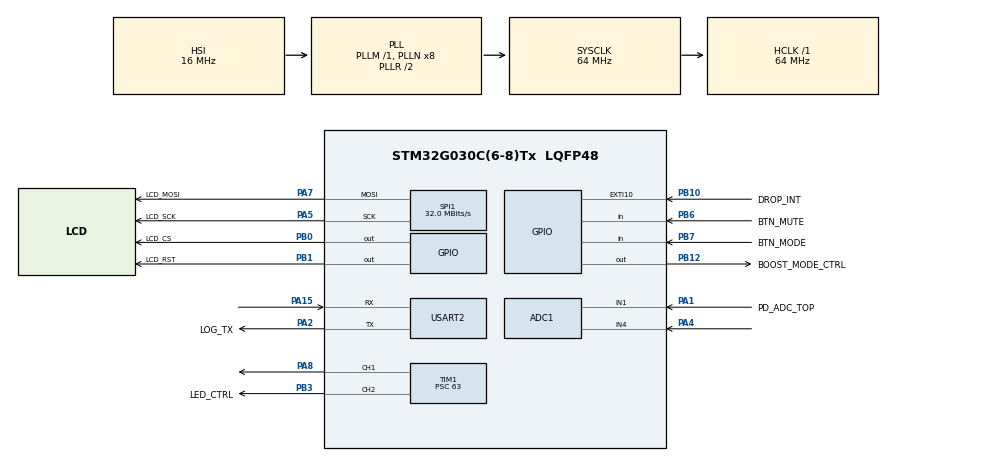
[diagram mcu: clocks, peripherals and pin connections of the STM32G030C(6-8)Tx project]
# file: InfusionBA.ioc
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ADC1.Channel-0\#ChannelRegularConversion=ADC_CHANNEL_1
ADC1.NbrOfConversionFlag=1
ADC1.Rank-0\#ChannelRegularConversion=1
ADC1.SamplingTime-0\#ChannelRegularConversion=ADC_SAMPLINGTIME_COMMON_1
ADC1.SelectedChannel=ADC_CHANNEL_1|ADC_CHANNEL_4
ADC1.master=1
Mcu.Family=STM32G0
Mcu.Name=STM32G030C(6-8)Tx
Mcu.Package=LQFP48
PA13.Mode=Serial_Wire
PA13.Signal=SYS_SWDIO
PA14-BOOT0.Mode=Serial_Wire
PA14-BOOT0.Signal=SYS_SWCLK
PA15.Mode=Asynchronous
PA15.Signal=USART2_RX
PA2.GPIO_Label=LOG_TX
PA2.Mode=Asynchronous
PA2.Signal=USART2_TX
PA1.GPIO_Label=PD_ADC_TOP
PA1.Mode=IN1
PA1.Signal=ADC1_IN1
PA4.Mode=IN4
PA4.Signal=ADC1_IN4
PA5.GPIO_Label=LCD_SCK
PA5.Mode=TX_Only_Simplex_Unidirect_Master
PA5.Signal=SPI1_SCK
PA7.GPIO_Label=LCD_MOSI
PA7.Mode=TX_Only_Simplex_Unidirect_Master
PA7.Signal=SPI1_MOSI
PA8.Signal=S_TIM1_CH1
PB0.GPIO_Label=LCD_CS
PB0.GPIO_ModeDefaultOutputPP=GPIO_MODE_OUTPUT_PP
PB0.GPIO_PuPd=GPIO_PULLUP
PB0.GPIO_Speed=GPIO_SPEED_FREQ_HIGH
PB0.Signal=GPIO_Output
PB1.GPIO_Label=LCD_RST
PB1.GPIO_ModeDefaultOutputPP=GPIO_MODE_OUTPUT_PP
PB1.GPIO_PuPd=GPIO_NOPULL
PB1.GPIO_Speed=GPIO_SPEED_FREQ_MEDIUM
PB1.Signal=GPIO_Output
PB10.GPIO_Label=DROP_INT
PB10.GPIO_ModeDefaultEXTI=GPIO_MODE_IT_FALLING
PB10.Signal=GPXTI10
PB12.GPIO_Label=BOOST_MODE_CTRL
PB12.GPIO_Speed=GPIO_SPEED_FREQ_MEDIUM
PB12.PinState=GPIO_PIN_SET
PB12.Signal=GPIO_Output
PB3.GPIO_Label=LED_CTRL
PB3.Signal=S_TIM1_CH2
PB6.GPIO_Label=BTN_MUTE
PB6.GPIO_PuPd=GPIO_PULLUP
PB6.Signal=GPIO_Input
PB7.GPIO_Label=BTN_MODE
PB7.GPIO_PuPd=GPIO_PULLUP
PB7.Signal=GPIO_Input
PC14-OSC32_IN\ (PC14).GPIO_Label=OSC32_IN
PC14-OSC32_IN\ (PC14).Mode=LSE-External-Oscillator
PC14-OSC32_IN\ (PC14).Signal=RCC_OSC32_IN
PC15-OSC32_OUT\ (PC15).GPIO_Label=OSC32_OUT
PC15-OSC32_OUT\ (PC15).Mode=LSE-External-Oscillator
PC15-OSC32_OUT\ (PC15).Signal=RCC_OSC32_OUT
ProjectManager.HeapSize=0x200
ProjectManager.StackSize=0x400
ProjectManager.TargetToolchain=STM32CubeIDE
RCC.ADCFreq_Value=64000000
RCC.AHBFreq_Value=64000000
RCC.CortexFreq_Value=64000000
RCC.EXTERNAL_CLOCK_VALUE=12288000
RCC.HCLKFreq_Value=64000000
RCC.HSE_VALUE=8000000
RCC.HSI_VALUE=16000000
RCC.SYSCLKFreq_VALUE=64000000
RCC.SYSCLKSource=RCC_SYSCLKSOURCE_PLLCLK
RCC.VCOOutputFreq_Value=128000000
SH.S_TIM1_CH1.0=TIM1_CH1,PWM Generation1 CH1
SH.S_TIM1_CH2.0=TIM1_CH2,PWM Generation2 CH2
SPI1.CalculateBaudRate=32.0 MBits/s
SPI1.Direction=SPI_DIRECTION_2LINES
SPI1.Mode=SPI_MODE_MASTER
SPI1.VirtualType=VM_MASTER
TIM1.AutoReloadPreload=TIM_AUTORELOAD_PRELOAD_ENABLE
TIM1.Channel-PWM\ Generation1\ CH1=TIM_CHANNEL_1
TIM1.Channel-PWM\ Generation2\ CH2=TIM_CHANNEL_2
TIM1.Period=249
TIM1.Prescaler=63
TIM1.Pulse-PWM\ Generation1\ CH1=0
USART2.VirtualMode-Asynchronous=VM_ASYNC
VP_RTC_VS_RTC_Activate.Mode=RTC_Enabled
board=custom

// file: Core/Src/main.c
/* USER CODE BEGIN Header */
/**
  ******************************************************************************
  * @file           : main.c
  * @brief          : Main program body
  ******************************************************************************
  * @attention
  *
  * Copyright (c) 2025 STMicroelectronics.
  * All rights reserved.
  *
  * This software is licensed under terms that can be found in the LICENSE file
  * in the root directory of this software component.
  * If no LICENSE file comes with this software, it is provided AS-IS.
  *
  ******************************************************************************
  */
/* USER CODE END Header */
#include "main.h"

/* USER CODE BEGIN PD */
#define BTN_MINUS_Pin GPIO_PIN_6
#define BTN_PLUS_Pin  GPIO_PIN_7
#define BTN_MODE_Pin  GPIO_PIN_8
#define BTN_MUTE_Pin  GPIO_PIN_9
#define BTN_PORT      GPIOB

/* ---------------- EA DOGS102 SPI DRIVER ---------------- */
#define DOG_CS_PORT   LCD_CS_GPIO_Port   // PB?
#define DOG_CS_PIN    LCD_CS_Pin
#define DOG_RST_PORT  GPIOB
#define DOG_RST_PIN   LCD_RST_Pin
#define DOG_CD_PORT   GPIOB             // D/C# wired to BOOST_MODE_CTRL_Pin
#define DOG_CD_PIN    BOOST_MODE_CTRL_Pin

/* USER CODE END PD */

ADC_HandleTypeDef hadc1;

RTC_HandleTypeDef hrtc;

SPI_HandleTypeDef hspi1;

TIM_HandleTypeDef htim1;

UART_HandleTypeDef huart2;

void SystemClock_Config(void);
static void MX_GPIO_Init(void);
static void MX_ADC1_Init(void);
static void MX_RTC_Init(void);
static void MX_SPI1_Init(void);
static void MX_TIM1_Init(void);
static void MX_USART2_UART_Init(void);

/* USER CODE BEGIN 0 */
static void Buzzer_SetDuty(uint16_t duty)
{
    __HAL_TIM_SET_COMPARE(&htim1, TIM_CHANNEL_1, duty);
}
void Buzzer_PlayFreq(uint16_t freq, uint16_t duration_ms)
{
    uint32_t timer_clk = 1000000;  // TIM1 clock after prescaler = 64 MHz / (63 + 1)
    uint32_t period = timer_clk / freq;

    __HAL_TIM_SET_AUTORELOAD(&htim1, period - 1);
    __HAL_TIM_SET_COMPARE(&htim1, TIM_CHANNEL_1, period / 2);  // 50% duty
    HAL_Delay(duration_ms);
    Buzzer_SetDuty(0);
}

/* USER CODE END 0 */

int main(void)
{

  /* MCU Configuration--------------------------------------------------------*/

  /* Reset of all peripherals, Initializes the Flash interface and the Systick. */
  HAL_Init();

  /* Configure the system clock */
  SystemClock_Config();

  /* Initialize all configured peripherals */
  MX_GPIO_Init();
  MX_ADC1_Init();
  MX_RTC_Init();
  MX_SPI1_Init();
  MX_TIM1_Init();
  MX_USART2_UART_Init();
  /* USER CODE BEGIN 2 */
  HAL_TIM_PWM_Start(&htim1, TIM_CHANNEL_1);
  /* USER CODE END 2 */

  /* Infinite loop */
  /* USER CODE BEGIN WHILE */
  while (1)
  {
	  if (HAL_GPIO_ReadPin(BTN_PORT, BTN_MINUS_Pin) == GPIO_PIN_RESET)
	      {
	          Buzzer_PlayFreq(3800, 100);  // 2 kHz, 100 ms

	          HAL_Delay(200);              // debounce
	      }

	      if (HAL_GPIO_ReadPin(BTN_PORT, BTN_PLUS_Pin) == GPIO_PIN_RESET)
	      {
	          Buzzer_PlayFreq(4000, 100);

	          HAL_Delay(200);
	      }

	      if (HAL_GPIO_ReadPin(BTN_PORT, BTN_MODE_Pin) == GPIO_PIN_RESET)
	      {
	          Buzzer_PlayFreq(4200, 100);

	          HAL_Delay(200);
	      }

	      if (HAL_GPIO_ReadPin(BTN_PORT, BTN_MUTE_Pin) == GPIO_PIN_RESET)
	      {
	          Buzzer_PlayFreq(4400, 100);

	          HAL_Delay(200);
	      }
    /* USER CODE END WHILE */

  }
}

void SystemClock_Config(void)
{
  RCC_OscInitTypeDef RCC_OscInitStruct = {0};
  RCC_ClkInitTypeDef RCC_ClkInitStruct = {0};
  RCC_PeriphCLKInitTypeDef PeriphClkInit = {0};

  /** Configure the main internal regulator output voltage
  */
  __HAL_RCC_PWR_CLK_ENABLE();
  HAL_PWREx_ControlVoltageScaling(PWR_REGULATOR_VOLTAGE_SCALE1);
  HAL_PWR_EnableBkUpAccess();
  __HAL_RCC_LSEDRIVE_CONFIG(RCC_LSEDRIVE_LOW);

  /** Initializes the RCC Oscillators according to the specified parameters
  * in the RCC_OscInitTypeDef structure.
  */
<<<<<<< HEAD
  RCC_OscInitStruct.OscillatorType = RCC_OSCILLATORTYPE_HSE|RCC_OSCILLATORTYPE_LSE;
  RCC_OscInitStruct.HSEState = RCC_HSE_ON;
  RCC_OscInitStruct.HSIState = RCC_HSI_OFF;
  RCC_OscInitStruct.LSEState = RCC_LSE_ON;
  RCC_OscInitStruct.LSIState = RCC_LSI_OFF;
=======
  RCC_OscInitStruct.OscillatorType = RCC_OSCILLATORTYPE_HSI|RCC_OSCILLATORTYPE_LSI;
  RCC_OscInitStruct.HSIState = RCC_HSI_ON;
  RCC_OscInitStruct.HSIDiv = RCC_HSI_DIV1;
  RCC_OscInitStruct.HSICalibrationValue = RCC_HSICALIBRATION_DEFAULT;
  RCC_OscInitStruct.LSIState = RCC_LSI_ON;
>>>>>>> parent of 39c39b9 (Switch to external oscillator)
  RCC_OscInitStruct.PLL.PLLState = RCC_PLL_ON;
  RCC_OscInitStruct.PLL.PLLSource = RCC_PLLSOURCE_HSI;
  RCC_OscInitStruct.PLL.PLLM = RCC_PLLM_DIV1;
  RCC_OscInitStruct.PLL.PLLN = 8;
  RCC_OscInitStruct.PLL.PLLP = RCC_PLLP_DIV2;
  RCC_OscInitStruct.PLL.PLLR = RCC_PLLR_DIV2;
  if (HAL_RCC_OscConfig(&RCC_OscInitStruct) != HAL_OK)
  {
    Error_Handler();
  }

  /** Configure RTC clock source */
  PeriphClkInit.PeriphClockSelection = RCC_PERIPHCLK_RTC;
  PeriphClkInit.RTCClockSelection = RCC_RTCCLKSOURCE_LSE;
  if (HAL_RCCEx_PeriphCLKConfig(&PeriphClkInit) != HAL_OK)
  {
    Error_Handler();
  }

  /** Initializes the CPU, AHB and APB buses clocks
  */
  RCC_ClkInitStruct.ClockType = RCC_CLOCKTYPE_HCLK|RCC_CLOCKTYPE_SYSCLK
                              |RCC_CLOCKTYPE_PCLK1;
  RCC_ClkInitStruct.SYSCLKSource = RCC_SYSCLKSOURCE_PLLCLK;
  RCC_ClkInitStruct.AHBCLKDivider = RCC_SYSCLK_DIV1;
  RCC_ClkInitStruct.APB1CLKDivider = RCC_HCLK_DIV1;

  if (HAL_RCC_ClockConfig(&RCC_ClkInitStruct, FLASH_LATENCY_2) != HAL_OK)
  {
    Error_Handler();
  }
}

static void MX_ADC1_Init(void)
{

  ADC_ChannelConfTypeDef sConfig = {0};

  /** Configure the global features of the ADC (Clock, Resolution, Data Alignment and number of conversion)
  */
  hadc1.Instance = ADC1;
  hadc1.Init.ClockPrescaler = ADC_CLOCK_SYNC_PCLK_DIV2;
  hadc1.Init.Resolution = ADC_RESOLUTION_12B;
  hadc1.Init.DataAlign = ADC_DATAALIGN_RIGHT;
  hadc1.Init.ScanConvMode = ADC_SCAN_DISABLE;
  hadc1.Init.EOCSelection = ADC_EOC_SINGLE_CONV;
  hadc1.Init.LowPowerAutoWait = DISABLE;
  hadc1.Init.LowPowerAutoPowerOff = DISABLE;
  hadc1.Init.ContinuousConvMode = DISABLE;
  hadc1.Init.NbrOfConversion = 1;
  hadc1.Init.DiscontinuousConvMode = DISABLE;
  hadc1.Init.ExternalTrigConv = ADC_SOFTWARE_START;
  hadc1.Init.ExternalTrigConvEdge = ADC_EXTERNALTRIGCONVEDGE_NONE;
  hadc1.Init.DMAContinuousRequests = DISABLE;
  hadc1.Init.Overrun = ADC_OVR_DATA_PRESERVED;
  hadc1.Init.SamplingTimeCommon1 = ADC_SAMPLETIME_1CYCLE_5;
  hadc1.Init.SamplingTimeCommon2 = ADC_SAMPLETIME_1CYCLE_5;
  hadc1.Init.OversamplingMode = DISABLE;
  hadc1.Init.TriggerFrequencyMode = ADC_TRIGGER_FREQ_HIGH;
  if (HAL_ADC_Init(&hadc1) != HAL_OK)
  {
    Error_Handler();
  }

  /** Configure Regular Channel
  */
  sConfig.Channel = ADC_CHANNEL_3;
  sConfig.Rank = ADC_REGULAR_RANK_1;
  sConfig.SamplingTime = ADC_SAMPLINGTIME_COMMON_1;
  if (HAL_ADC_ConfigChannel(&hadc1, &sConfig) != HAL_OK)
  {
    Error_Handler();
  }

}

static void MX_RTC_Init(void)
{

  /** Initialize RTC Only
  */
  hrtc.Instance = RTC;
  hrtc.Init.HourFormat = RTC_HOURFORMAT_24;
  hrtc.Init.AsynchPrediv = 127;
  hrtc.Init.SynchPrediv = 255;
  hrtc.Init.OutPut = RTC_OUTPUT_DISABLE;
  hrtc.Init.OutPutRemap = RTC_OUTPUT_REMAP_NONE;
  hrtc.Init.OutPutPolarity = RTC_OUTPUT_POLARITY_HIGH;
  hrtc.Init.OutPutType = RTC_OUTPUT_TYPE_OPENDRAIN;
  hrtc.Init.OutPutPullUp = RTC_OUTPUT_PULLUP_NONE;
  if (HAL_RTC_Init(&hrtc) != HAL_OK)
  {
    Error_Handler();
  }

}

static void MX_SPI1_Init(void)
{

  /* SPI1 parameter configuration*/
  hspi1.Instance = SPI1;
  hspi1.Init.Mode = SPI_MODE_MASTER;
  hspi1.Init.Direction = SPI_DIRECTION_2LINES;
  hspi1.Init.DataSize = SPI_DATASIZE_8BIT;
  hspi1.Init.CLKPolarity = SPI_POLARITY_LOW;
  hspi1.Init.CLKPhase = SPI_PHASE_1EDGE;
  hspi1.Init.NSS = SPI_NSS_SOFT;
  hspi1.Init.BaudRatePrescaler = SPI_BAUDRATEPRESCALER_2;
  hspi1.Init.FirstBit = SPI_FIRSTBIT_MSB;
  hspi1.Init.TIMode = SPI_TIMODE_DISABLE;
  hspi1.Init.CRCCalculation = SPI_CRCCALCULATION_DISABLE;
  hspi1.Init.CRCPolynomial = 7;
  hspi1.Init.CRCLength = SPI_CRC_LENGTH_DATASIZE;
  hspi1.Init.NSSPMode = SPI_NSS_PULSE_ENABLE;
  if (HAL_SPI_Init(&hspi1) != HAL_OK)
  {
    Error_Handler();
  }

}

static void MX_TIM1_Init(void)
{

  TIM_MasterConfigTypeDef sMasterConfig = {0};
  TIM_OC_InitTypeDef sConfigOC = {0};
  TIM_BreakDeadTimeConfigTypeDef sBreakDeadTimeConfig = {0};

  htim1.Instance = TIM1;
  htim1.Init.Prescaler = 63;
  htim1.Init.CounterMode = TIM_COUNTERMODE_UP;
  htim1.Init.Period = 249;
  htim1.Init.ClockDivision = TIM_CLOCKDIVISION_DIV1;
  htim1.Init.RepetitionCounter = 0;
  htim1.Init.AutoReloadPreload = TIM_AUTORELOAD_PRELOAD_ENABLE;
  if (HAL_TIM_PWM_Init(&htim1) != HAL_OK)
  {
    Error_Handler();
  }
  sMasterConfig.MasterOutputTrigger = TIM_TRGO_RESET;
  sMasterConfig.MasterOutputTrigger2 = TIM_TRGO2_RESET;
  sMasterConfig.MasterSlaveMode = TIM_MASTERSLAVEMODE_DISABLE;
  if (HAL_TIMEx_MasterConfigSynchronization(&htim1, &sMasterConfig) != HAL_OK)
  {
    Error_Handler();
  }
  sConfigOC.OCMode = TIM_OCMODE_PWM1;
  sConfigOC.Pulse = 0;
  sConfigOC.OCPolarity = TIM_OCPOLARITY_HIGH;
  sConfigOC.OCNPolarity = TIM_OCNPOLARITY_HIGH;
  sConfigOC.OCFastMode = TIM_OCFAST_DISABLE;
  sConfigOC.OCIdleState = TIM_OCIDLESTATE_RESET;
  sConfigOC.OCNIdleState = TIM_OCNIDLESTATE_RESET;
  if (HAL_TIM_PWM_ConfigChannel(&htim1, &sConfigOC, TIM_CHANNEL_1) != HAL_OK)
  {
    Error_Handler();
  }
  if (HAL_TIM_PWM_ConfigChannel(&htim1, &sConfigOC, TIM_CHANNEL_2) != HAL_OK)
  {
    Error_Handler();
  }
  sBreakDeadTimeConfig.OffStateRunMode = TIM_OSSR_DISABLE;
  sBreakDeadTimeConfig.OffStateIDLEMode = TIM_OSSI_DISABLE;
  sBreakDeadTimeConfig.LockLevel = TIM_LOCKLEVEL_OFF;
  sBreakDeadTimeConfig.DeadTime = 0;
  sBreakDeadTimeConfig.BreakState = TIM_BREAK_DISABLE;
  sBreakDeadTimeConfig.BreakPolarity = TIM_BREAKPOLARITY_HIGH;
  sBreakDeadTimeConfig.BreakFilter = 0;
  sBreakDeadTimeConfig.BreakAFMode = TIM_BREAK_AFMODE_INPUT;
  sBreakDeadTimeConfig.Break2State = TIM_BREAK2_DISABLE;
  sBreakDeadTimeConfig.Break2Polarity = TIM_BREAK2POLARITY_HIGH;
  sBreakDeadTimeConfig.Break2Filter = 0;
  sBreakDeadTimeConfig.Break2AFMode = TIM_BREAK_AFMODE_INPUT;
  sBreakDeadTimeConfig.AutomaticOutput = TIM_AUTOMATICOUTPUT_DISABLE;
  if (HAL_TIMEx_ConfigBreakDeadTime(&htim1, &sBreakDeadTimeConfig) != HAL_OK)
  {
    Error_Handler();
  }
  HAL_TIM_MspPostInit(&htim1);

}

static void MX_USART2_UART_Init(void)
{

  huart2.Instance = USART2;
  huart2.Init.BaudRate = 115200;
  huart2.Init.WordLength = UART_WORDLENGTH_8B;
  huart2.Init.StopBits = UART_STOPBITS_1;
  huart2.Init.Parity = UART_PARITY_NONE;
  huart2.Init.Mode = UART_MODE_TX_RX;
  huart2.Init.HwFlowCtl = UART_HWCONTROL_NONE;
  huart2.Init.OverSampling = UART_OVERSAMPLING_16;
  huart2.Init.OneBitSampling = UART_ONE_BIT_SAMPLE_DISABLE;
  huart2.Init.ClockPrescaler = UART_PRESCALER_DIV1;
  huart2.AdvancedInit.AdvFeatureInit = UART_ADVFEATURE_NO_INIT;
  if (HAL_UART_Init(&huart2) != HAL_OK)
  {
    Error_Handler();
  }

}

static void MX_GPIO_Init(void)
{
  GPIO_InitTypeDef GPIO_InitStruct = {0};

  /* GPIO Ports Clock Enable */
  __HAL_RCC_GPIOC_CLK_ENABLE();
  __HAL_RCC_GPIOA_CLK_ENABLE();
  __HAL_RCC_GPIOB_CLK_ENABLE();

  /*Configure GPIO pin Output Level */
  HAL_GPIO_WritePin(GPIOB, LCD_CS_Pin|LCD_RST_Pin, GPIO_PIN_RESET);

  /*Configure GPIO pin Output Level */
  HAL_GPIO_WritePin(BOOST_MODE_CTRL_GPIO_Port, BOOST_MODE_CTRL_Pin, GPIO_PIN_SET);

  /*Configure GPIO pin : LCD_CS_Pin */
  GPIO_InitStruct.Pin = LCD_CS_Pin;
  GPIO_InitStruct.Mode = GPIO_MODE_OUTPUT_PP;
  GPIO_InitStruct.Pull = GPIO_PULLUP;
  GPIO_InitStruct.Speed = GPIO_SPEED_FREQ_HIGH;
  HAL_GPIO_Init(LCD_CS_GPIO_Port, &GPIO_InitStruct);

  /*Configure GPIO pins : LCD_RST_Pin BOOST_MODE_CTRL_Pin */
  GPIO_InitStruct.Pin = LCD_RST_Pin|BOOST_MODE_CTRL_Pin;
  GPIO_InitStruct.Mode = GPIO_MODE_OUTPUT_PP;
  GPIO_InitStruct.Pull = GPIO_NOPULL;
  GPIO_InitStruct.Speed = GPIO_SPEED_FREQ_MEDIUM;
  HAL_GPIO_Init(GPIOB, &GPIO_InitStruct);

  /*Configure GPIO pin : DROP_INT_Pin */
  GPIO_InitStruct.Pin = DROP_INT_Pin;
  GPIO_InitStruct.Mode = GPIO_MODE_IT_FALLING;
  GPIO_InitStruct.Pull = GPIO_NOPULL;
  HAL_GPIO_Init(DROP_INT_GPIO_Port, &GPIO_InitStruct);

  /*Configure GPIO pins : BTN_MINUS_Pin BTN_PLUS_Pin BTN_MODE_Pin BTN_MUTE_Pin */
  GPIO_InitStruct.Pin = BTN_MINUS_Pin|BTN_PLUS_Pin|BTN_MODE_Pin|BTN_MUTE_Pin;
  GPIO_InitStruct.Mode = GPIO_MODE_INPUT;
  GPIO_InitStruct.Pull = GPIO_PULLUP;
  HAL_GPIO_Init(GPIOB, &GPIO_InitStruct);

}

void Error_Handler(void)
{
  __disable_irq();
  while (1)
  {
  }
}
